One B-rep face of a CAD part: STEP entity #70670.
In plain terms, the planar face has unit normal (0, 0, 1).
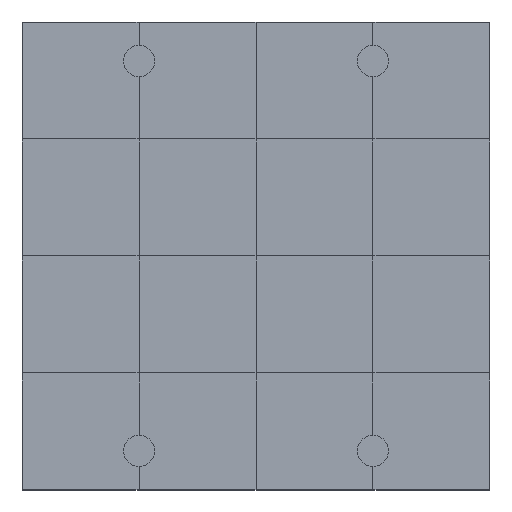
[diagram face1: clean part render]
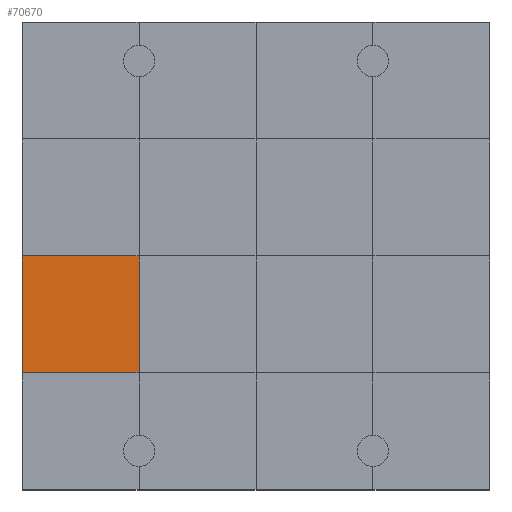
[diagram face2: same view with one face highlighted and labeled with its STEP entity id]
Its self-contained STEP definition (entity closure, numbers rounded to 3 decimals):
#70220 = VERTEX_POINT('',#70221);
#70221 = CARTESIAN_POINT('',(0.,3.,1.2));
#70235 = PLANE('',#70236);
#70236 = AXIS2_PLACEMENT_3D('',#70237,#70238,#70239);
#70237 = CARTESIAN_POINT('',(0.,3.,0.));
#70238 = DIRECTION('',(1.,0.,-0.));
#70239 = DIRECTION('',(0.,0.,1.));
#70261 = PLANE('',#70262);
#70262 = AXIS2_PLACEMENT_3D('',#70263,#70264,#70265);
#70263 = CARTESIAN_POINT('',(0.,0.,1.2));
#70264 = DIRECTION('',(0.,0.,1.));
#70265 = DIRECTION('',(1.,0.,-0.));
#70412 = VERTEX_POINT('',#70413);
#70413 = CARTESIAN_POINT('',(3.,3.,1.2));
#70434 = EDGE_CURVE('',#70220,#70412,#70435,.T.);
#70435 = SURFACE_CURVE('',#70436,(#70440,#70447),.PCURVE_S1.);
#70436 = LINE('',#70437,#70438);
#70437 = CARTESIAN_POINT('',(0.,3.,1.2));
#70438 = VECTOR('',#70439,1.);
#70439 = DIRECTION('',(1.,0.,-0.));
#70440 = PCURVE('',#70261,#70441);
#70441 = DEFINITIONAL_REPRESENTATION('',(#70442),#70446);
#70442 = LINE('',#70443,#70444);
#70443 = CARTESIAN_POINT('',(0.,3.));
#70444 = VECTOR('',#70445,1.);
#70445 = DIRECTION('',(1.,0.));
#70446 = ( GEOMETRIC_REPRESENTATION_CONTEXT(2) 
PARAMETRIC_REPRESENTATION_CONTEXT() REPRESENTATION_CONTEXT('2D SPACE',''
  ) );
#70447 = PCURVE('',#70448,#70453);
#70448 = PLANE('',#70449);
#70449 = AXIS2_PLACEMENT_3D('',#70450,#70451,#70452);
#70450 = CARTESIAN_POINT('',(0.,3.,1.2));
#70451 = DIRECTION('',(0.,0.,1.));
#70452 = DIRECTION('',(1.,0.,-0.));
#70453 = DEFINITIONAL_REPRESENTATION('',(#70454),#70458);
#70454 = LINE('',#70455,#70456);
#70455 = CARTESIAN_POINT('',(0.,0.));
#70456 = VECTOR('',#70457,1.);
#70457 = DIRECTION('',(1.,0.));
#70458 = ( GEOMETRIC_REPRESENTATION_CONTEXT(2) 
PARAMETRIC_REPRESENTATION_CONTEXT() REPRESENTATION_CONTEXT('2D SPACE',''
  ) );
#70493 = VERTEX_POINT('',#70494);
#70494 = CARTESIAN_POINT('',(0.,6.,1.2));
#70520 = EDGE_CURVE('',#70220,#70493,#70521,.T.);
#70521 = SURFACE_CURVE('',#70522,(#70526,#70533),.PCURVE_S1.);
#70522 = LINE('',#70523,#70524);
#70523 = CARTESIAN_POINT('',(0.,3.,1.2));
#70524 = VECTOR('',#70525,1.);
#70525 = DIRECTION('',(-0.,1.,0.));
#70526 = PCURVE('',#70235,#70527);
#70527 = DEFINITIONAL_REPRESENTATION('',(#70528),#70532);
#70528 = LINE('',#70529,#70530);
#70529 = CARTESIAN_POINT('',(1.2,0.));
#70530 = VECTOR('',#70531,1.);
#70531 = DIRECTION('',(0.,-1.));
#70532 = ( GEOMETRIC_REPRESENTATION_CONTEXT(2) 
PARAMETRIC_REPRESENTATION_CONTEXT() REPRESENTATION_CONTEXT('2D SPACE',''
  ) );
#70533 = PCURVE('',#70448,#70534);
#70534 = DEFINITIONAL_REPRESENTATION('',(#70535),#70539);
#70535 = LINE('',#70536,#70537);
#70536 = CARTESIAN_POINT('',(0.,0.));
#70537 = VECTOR('',#70538,1.);
#70538 = DIRECTION('',(0.,1.));
#70539 = ( GEOMETRIC_REPRESENTATION_CONTEXT(2) 
PARAMETRIC_REPRESENTATION_CONTEXT() REPRESENTATION_CONTEXT('2D SPACE',''
  ) );
#70670 = ADVANCED_FACE('',(#70671),#70448,.T.);
#70671 = FACE_BOUND('',#70672,.T.);
#70672 = EDGE_LOOP('',(#70673,#70674,#70675,#70703));
#70673 = ORIENTED_EDGE('',*,*,#70520,.F.);
#70674 = ORIENTED_EDGE('',*,*,#70434,.T.);
#70675 = ORIENTED_EDGE('',*,*,#70676,.T.);
#70676 = EDGE_CURVE('',#70412,#70677,#70679,.T.);
#70677 = VERTEX_POINT('',#70678);
#70678 = CARTESIAN_POINT('',(3.,6.,1.2));
#70679 = SURFACE_CURVE('',#70680,(#70684,#70691),.PCURVE_S1.);
#70680 = LINE('',#70681,#70682);
#70681 = CARTESIAN_POINT('',(3.,3.,1.2));
#70682 = VECTOR('',#70683,1.);
#70683 = DIRECTION('',(-0.,1.,0.));
#70684 = PCURVE('',#70448,#70685);
#70685 = DEFINITIONAL_REPRESENTATION('',(#70686),#70690);
#70686 = LINE('',#70687,#70688);
#70687 = CARTESIAN_POINT('',(3.,0.));
#70688 = VECTOR('',#70689,1.);
#70689 = DIRECTION('',(0.,1.));
#70690 = ( GEOMETRIC_REPRESENTATION_CONTEXT(2) 
PARAMETRIC_REPRESENTATION_CONTEXT() REPRESENTATION_CONTEXT('2D SPACE',''
  ) );
#70691 = PCURVE('',#70692,#70697);
#70692 = PLANE('',#70693);
#70693 = AXIS2_PLACEMENT_3D('',#70694,#70695,#70696);
#70694 = CARTESIAN_POINT('',(3.,3.,1.2));
#70695 = DIRECTION('',(0.,0.,1.));
#70696 = DIRECTION('',(1.,0.,-0.));
#70697 = DEFINITIONAL_REPRESENTATION('',(#70698),#70702);
#70698 = LINE('',#70699,#70700);
#70699 = CARTESIAN_POINT('',(0.,0.));
#70700 = VECTOR('',#70701,1.);
#70701 = DIRECTION('',(0.,1.));
#70702 = ( GEOMETRIC_REPRESENTATION_CONTEXT(2) 
PARAMETRIC_REPRESENTATION_CONTEXT() REPRESENTATION_CONTEXT('2D SPACE',''
  ) );
#70703 = ORIENTED_EDGE('',*,*,#70704,.F.);
#70704 = EDGE_CURVE('',#70493,#70677,#70705,.T.);
#70705 = SURFACE_CURVE('',#70706,(#70710,#70717),.PCURVE_S1.);
#70706 = LINE('',#70707,#70708);
#70707 = CARTESIAN_POINT('',(0.,6.,1.2));
#70708 = VECTOR('',#70709,1.);
#70709 = DIRECTION('',(1.,0.,-0.));
#70710 = PCURVE('',#70448,#70711);
#70711 = DEFINITIONAL_REPRESENTATION('',(#70712),#70716);
#70712 = LINE('',#70713,#70714);
#70713 = CARTESIAN_POINT('',(0.,3.));
#70714 = VECTOR('',#70715,1.);
#70715 = DIRECTION('',(1.,0.));
#70716 = ( GEOMETRIC_REPRESENTATION_CONTEXT(2) 
PARAMETRIC_REPRESENTATION_CONTEXT() REPRESENTATION_CONTEXT('2D SPACE',''
  ) );
#70717 = PCURVE('',#70718,#70723);
#70718 = PLANE('',#70719);
#70719 = AXIS2_PLACEMENT_3D('',#70720,#70721,#70722);
#70720 = CARTESIAN_POINT('',(0.,6.,1.2));
#70721 = DIRECTION('',(0.,0.,1.));
#70722 = DIRECTION('',(1.,0.,-0.));
#70723 = DEFINITIONAL_REPRESENTATION('',(#70724),#70728);
#70724 = LINE('',#70725,#70726);
#70725 = CARTESIAN_POINT('',(0.,0.));
#70726 = VECTOR('',#70727,1.);
#70727 = DIRECTION('',(1.,0.));
#70728 = ( GEOMETRIC_REPRESENTATION_CONTEXT(2) 
PARAMETRIC_REPRESENTATION_CONTEXT() REPRESENTATION_CONTEXT('2D SPACE',''
  ) );
